# Generated by FakeRAM 2.0 (routing-friendly)
VERSION 5.7 ;
BUSBITCHARS "[]" ;
PROPERTYDEFINITIONS
  MACRO width INTEGER ;
  MACRO depth INTEGER ;
  MACRO banks INTEGER ;
END PROPERTYDEFINITIONS
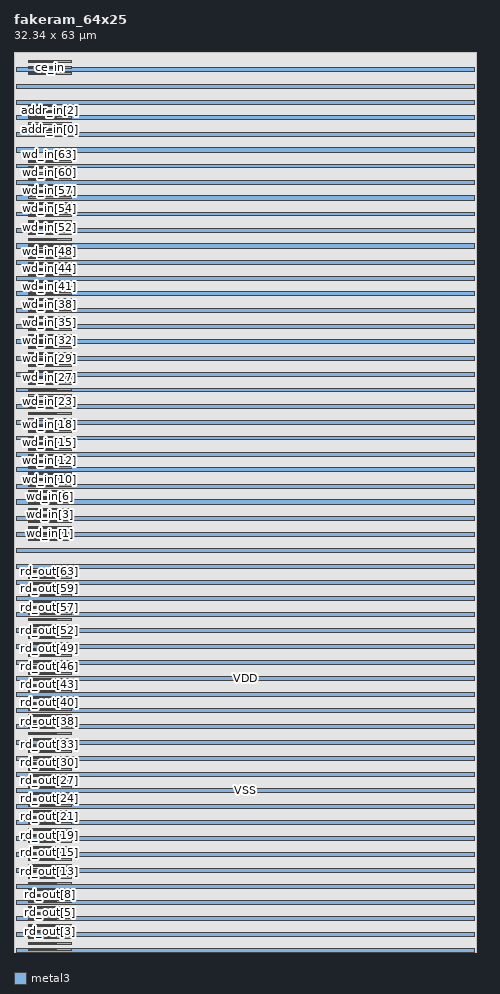
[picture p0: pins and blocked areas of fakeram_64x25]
MACRO fakeram_64x25
  PROPERTY width 64 ;
  PROPERTY depth 25 ;
  PROPERTY banks 1 ;
  FOREIGN fakeram_64x25 0 0 ;
  SYMMETRY X Y R90 ;
  SIZE 32.340 BY 63.000 ;
  CLASS BLOCK ;
  PIN rd_out[0]
    DIRECTION OUTPUT ;
    USE SIGNAL ;
    PORT
      LAYER metal3 ;
      RECT 1.000 0.140 3.000 0.210 ;
    END
    PORT
      LAYER metal3 ;
      RECT 1.000 0.105 4.000 0.245 ;
    END
  END rd_out[0]
  PIN rd_out[1]
    DIRECTION OUTPUT ;
    USE SIGNAL ;
    PORT
      LAYER metal3 ;
      RECT 1.000 0.560 3.000 0.630 ;
    END
    PORT
      LAYER metal3 ;
      RECT 1.000 0.525 4.000 0.665 ;
    END
  END rd_out[1]
  PIN rd_out[2]
    DIRECTION OUTPUT ;
    USE SIGNAL ;
    PORT
      LAYER metal3 ;
      RECT 1.000 0.980 3.000 1.050 ;
    END
    PORT
      LAYER metal3 ;
      RECT 1.000 0.945 4.000 1.085 ;
    END
  END rd_out[2]
  PIN rd_out[3]
    DIRECTION OUTPUT ;
    USE SIGNAL ;
    PORT
      LAYER metal3 ;
      RECT 1.000 1.400 3.000 1.470 ;
    END
    PORT
      LAYER metal3 ;
      RECT 1.000 1.365 4.000 1.505 ;
    END
  END rd_out[3]
  PIN rd_out[4]
    DIRECTION OUTPUT ;
    USE SIGNAL ;
    PORT
      LAYER metal3 ;
      RECT 1.000 1.820 3.000 1.890 ;
    END
    PORT
      LAYER metal3 ;
      RECT 1.000 1.785 4.000 1.925 ;
    END
  END rd_out[4]
  PIN rd_out[5]
    DIRECTION OUTPUT ;
    USE SIGNAL ;
    PORT
      LAYER metal3 ;
      RECT 1.000 2.240 3.000 2.310 ;
    END
    PORT
      LAYER metal3 ;
      RECT 1.000 2.205 4.000 2.345 ;
    END
  END rd_out[5]
  PIN rd_out[6]
    DIRECTION OUTPUT ;
    USE SIGNAL ;
    PORT
      LAYER metal3 ;
      RECT 1.000 2.660 3.000 2.730 ;
    END
    PORT
      LAYER metal3 ;
      RECT 1.000 2.625 4.000 2.765 ;
    END
  END rd_out[6]
  PIN rd_out[7]
    DIRECTION OUTPUT ;
    USE SIGNAL ;
    PORT
      LAYER metal3 ;
      RECT 1.000 3.080 3.000 3.150 ;
    END
    PORT
      LAYER metal3 ;
      RECT 1.000 3.045 4.000 3.185 ;
    END
  END rd_out[7]
  PIN rd_out[8]
    DIRECTION OUTPUT ;
    USE SIGNAL ;
    PORT
      LAYER metal3 ;
      RECT 1.000 3.500 3.000 3.570 ;
    END
    PORT
      LAYER metal3 ;
      RECT 1.000 3.465 4.000 3.605 ;
    END
  END rd_out[8]
  PIN rd_out[9]
    DIRECTION OUTPUT ;
    USE SIGNAL ;
    PORT
      LAYER metal3 ;
      RECT 1.000 3.920 3.000 3.990 ;
    END
    PORT
      LAYER metal3 ;
      RECT 1.000 3.885 4.000 4.025 ;
    END
  END rd_out[9]
  PIN rd_out[10]
    DIRECTION OUTPUT ;
    USE SIGNAL ;
    PORT
      LAYER metal3 ;
      RECT 1.000 4.340 3.000 4.410 ;
    END
    PORT
      LAYER metal3 ;
      RECT 1.000 4.305 4.000 4.445 ;
    END
  END rd_out[10]
  PIN rd_out[11]
    DIRECTION OUTPUT ;
    USE SIGNAL ;
    PORT
      LAYER metal3 ;
      RECT 1.000 4.760 3.000 4.830 ;
    END
    PORT
      LAYER metal3 ;
      RECT 1.000 4.725 4.000 4.865 ;
    END
  END rd_out[11]
  PIN rd_out[12]
    DIRECTION OUTPUT ;
    USE SIGNAL ;
    PORT
      LAYER metal3 ;
      RECT 1.000 5.180 3.000 5.250 ;
    END
    PORT
      LAYER metal3 ;
      RECT 1.000 5.145 4.000 5.285 ;
    END
  END rd_out[12]
  PIN rd_out[13]
    DIRECTION OUTPUT ;
    USE SIGNAL ;
    PORT
      LAYER metal3 ;
      RECT 1.000 5.600 3.000 5.670 ;
    END
    PORT
      LAYER metal3 ;
      RECT 1.000 5.565 4.000 5.705 ;
    END
  END rd_out[13]
  PIN rd_out[14]
    DIRECTION OUTPUT ;
    USE SIGNAL ;
    PORT
      LAYER metal3 ;
      RECT 1.000 6.020 3.000 6.090 ;
    END
    PORT
      LAYER metal3 ;
      RECT 1.000 5.985 4.000 6.125 ;
    END
  END rd_out[14]
  PIN rd_out[15]
    DIRECTION OUTPUT ;
    USE SIGNAL ;
    PORT
      LAYER metal3 ;
      RECT 1.000 6.440 3.000 6.510 ;
    END
    PORT
      LAYER metal3 ;
      RECT 1.000 6.405 4.000 6.545 ;
    END
  END rd_out[15]
  PIN rd_out[16]
    DIRECTION OUTPUT ;
    USE SIGNAL ;
    PORT
      LAYER metal3 ;
      RECT 1.000 6.860 3.000 6.930 ;
    END
    PORT
      LAYER metal3 ;
      RECT 1.000 6.825 4.000 6.965 ;
    END
  END rd_out[16]
  PIN rd_out[17]
    DIRECTION OUTPUT ;
    USE SIGNAL ;
    PORT
      LAYER metal3 ;
      RECT 1.000 7.280 3.000 7.350 ;
    END
    PORT
      LAYER metal3 ;
      RECT 1.000 7.245 4.000 7.385 ;
    END
  END rd_out[17]
  PIN rd_out[18]
    DIRECTION OUTPUT ;
    USE SIGNAL ;
    PORT
      LAYER metal3 ;
      RECT 1.000 7.700 3.000 7.770 ;
    END
    PORT
      LAYER metal3 ;
      RECT 1.000 7.665 4.000 7.805 ;
    END
  END rd_out[18]
  PIN rd_out[19]
    DIRECTION OUTPUT ;
    USE SIGNAL ;
    PORT
      LAYER metal3 ;
      RECT 1.000 8.120 3.000 8.190 ;
    END
    PORT
      LAYER metal3 ;
      RECT 1.000 8.085 4.000 8.225 ;
    END
  END rd_out[19]
  PIN rd_out[20]
    DIRECTION OUTPUT ;
    USE SIGNAL ;
    PORT
      LAYER metal3 ;
      RECT 1.000 8.540 3.000 8.610 ;
    END
    PORT
      LAYER metal3 ;
      RECT 1.000 8.505 4.000 8.645 ;
    END
  END rd_out[20]
  PIN rd_out[21]
    DIRECTION OUTPUT ;
    USE SIGNAL ;
    PORT
      LAYER metal3 ;
      RECT 1.000 8.960 3.000 9.030 ;
    END
    PORT
      LAYER metal3 ;
      RECT 1.000 8.925 4.000 9.065 ;
    END
  END rd_out[21]
  PIN rd_out[22]
    DIRECTION OUTPUT ;
    USE SIGNAL ;
    PORT
      LAYER metal3 ;
      RECT 1.000 9.380 3.000 9.450 ;
    END
    PORT
      LAYER metal3 ;
      RECT 1.000 9.345 4.000 9.485 ;
    END
  END rd_out[22]
  PIN rd_out[23]
    DIRECTION OUTPUT ;
    USE SIGNAL ;
    PORT
      LAYER metal3 ;
      RECT 1.000 9.800 3.000 9.870 ;
    END
    PORT
      LAYER metal3 ;
      RECT 1.000 9.765 4.000 9.905 ;
    END
  END rd_out[23]
  PIN rd_out[24]
    DIRECTION OUTPUT ;
    USE SIGNAL ;
    PORT
      LAYER metal3 ;
      RECT 1.000 10.220 3.000 10.290 ;
    END
    PORT
      LAYER metal3 ;
      RECT 1.000 10.185 4.000 10.325 ;
    END
  END rd_out[24]
  PIN rd_out[25]
    DIRECTION OUTPUT ;
    USE SIGNAL ;
    PORT
      LAYER metal3 ;
      RECT 1.000 10.640 3.000 10.710 ;
    END
    PORT
      LAYER metal3 ;
      RECT 1.000 10.605 4.000 10.745 ;
    END
  END rd_out[25]
  PIN rd_out[26]
    DIRECTION OUTPUT ;
    USE SIGNAL ;
    PORT
      LAYER metal3 ;
      RECT 1.000 11.060 3.000 11.130 ;
    END
    PORT
      LAYER metal3 ;
      RECT 1.000 11.025 4.000 11.165 ;
    END
  END rd_out[26]
  PIN rd_out[27]
    DIRECTION OUTPUT ;
    USE SIGNAL ;
    PORT
      LAYER metal3 ;
      RECT 1.000 11.480 3.000 11.550 ;
    END
    PORT
      LAYER metal3 ;
      RECT 1.000 11.445 4.000 11.585 ;
    END
  END rd_out[27]
  PIN rd_out[28]
    DIRECTION OUTPUT ;
    USE SIGNAL ;
    PORT
      LAYER metal3 ;
      RECT 1.000 11.900 3.000 11.970 ;
    END
    PORT
      LAYER metal3 ;
      RECT 1.000 11.865 4.000 12.005 ;
    END
  END rd_out[28]
  PIN rd_out[29]
    DIRECTION OUTPUT ;
    USE SIGNAL ;
    PORT
      LAYER metal3 ;
      RECT 1.000 12.320 3.000 12.390 ;
    END
    PORT
      LAYER metal3 ;
      RECT 1.000 12.285 4.000 12.425 ;
    END
  END rd_out[29]
  PIN rd_out[30]
    DIRECTION OUTPUT ;
    USE SIGNAL ;
    PORT
      LAYER metal3 ;
      RECT 1.000 12.740 3.000 12.810 ;
    END
    PORT
      LAYER metal3 ;
      RECT 1.000 12.705 4.000 12.845 ;
    END
  END rd_out[30]
  PIN rd_out[31]
    DIRECTION OUTPUT ;
    USE SIGNAL ;
    PORT
      LAYER metal3 ;
      RECT 1.000 13.160 3.000 13.230 ;
    END
    PORT
      LAYER metal3 ;
      RECT 1.000 13.125 4.000 13.265 ;
    END
  END rd_out[31]
  PIN rd_out[32]
    DIRECTION OUTPUT ;
    USE SIGNAL ;
    PORT
      LAYER metal3 ;
      RECT 1.000 13.580 3.000 13.650 ;
    END
    PORT
      LAYER metal3 ;
      RECT 1.000 13.545 4.000 13.685 ;
    END
  END rd_out[32]
  PIN rd_out[33]
    DIRECTION OUTPUT ;
    USE SIGNAL ;
    PORT
      LAYER metal3 ;
      RECT 1.000 14.000 3.000 14.070 ;
    END
    PORT
      LAYER metal3 ;
      RECT 1.000 13.965 4.000 14.105 ;
    END
  END rd_out[33]
  PIN rd_out[34]
    DIRECTION OUTPUT ;
    USE SIGNAL ;
    PORT
      LAYER metal3 ;
      RECT 1.000 14.420 3.000 14.490 ;
    END
    PORT
      LAYER metal3 ;
      RECT 1.000 14.385 4.000 14.525 ;
    END
  END rd_out[34]
  PIN rd_out[35]
    DIRECTION OUTPUT ;
    USE SIGNAL ;
    PORT
      LAYER metal3 ;
      RECT 1.000 14.840 3.000 14.910 ;
    END
    PORT
      LAYER metal3 ;
      RECT 1.000 14.805 4.000 14.945 ;
    END
  END rd_out[35]
  PIN rd_out[36]
    DIRECTION OUTPUT ;
    USE SIGNAL ;
    PORT
      LAYER metal3 ;
      RECT 1.000 15.260 3.000 15.330 ;
    END
    PORT
      LAYER metal3 ;
      RECT 1.000 15.225 4.000 15.365 ;
    END
  END rd_out[36]
  PIN rd_out[37]
    DIRECTION OUTPUT ;
    USE SIGNAL ;
    PORT
      LAYER metal3 ;
      RECT 1.000 15.680 3.000 15.750 ;
    END
    PORT
      LAYER metal3 ;
      RECT 1.000 15.645 4.000 15.785 ;
    END
  END rd_out[37]
  PIN rd_out[38]
    DIRECTION OUTPUT ;
    USE SIGNAL ;
    PORT
      LAYER metal3 ;
      RECT 1.000 16.100 3.000 16.170 ;
    END
    PORT
      LAYER metal3 ;
      RECT 1.000 16.065 4.000 16.205 ;
    END
  END rd_out[38]
  PIN rd_out[39]
    DIRECTION OUTPUT ;
    USE SIGNAL ;
    PORT
      LAYER metal3 ;
      RECT 1.000 16.520 3.000 16.590 ;
    END
    PORT
      LAYER metal3 ;
      RECT 1.000 16.485 4.000 16.625 ;
    END
  END rd_out[39]
  PIN rd_out[40]
    DIRECTION OUTPUT ;
    USE SIGNAL ;
    PORT
      LAYER metal3 ;
      RECT 1.000 16.940 3.000 17.010 ;
    END
    PORT
      LAYER metal3 ;
      RECT 1.000 16.905 4.000 17.045 ;
    END
  END rd_out[40]
  PIN rd_out[41]
    DIRECTION OUTPUT ;
    USE SIGNAL ;
    PORT
      LAYER metal3 ;
      RECT 1.000 17.360 3.000 17.430 ;
    END
    PORT
      LAYER metal3 ;
      RECT 1.000 17.325 4.000 17.465 ;
    END
  END rd_out[41]
  PIN rd_out[42]
    DIRECTION OUTPUT ;
    USE SIGNAL ;
    PORT
      LAYER metal3 ;
      RECT 1.000 17.780 3.000 17.850 ;
    END
    PORT
      LAYER metal3 ;
      RECT 1.000 17.745 4.000 17.885 ;
    END
  END rd_out[42]
  PIN rd_out[43]
    DIRECTION OUTPUT ;
    USE SIGNAL ;
    PORT
      LAYER metal3 ;
      RECT 1.000 18.200 3.000 18.270 ;
    END
    PORT
      LAYER metal3 ;
      RECT 1.000 18.165 4.000 18.305 ;
    END
  END rd_out[43]
  PIN rd_out[44]
    DIRECTION OUTPUT ;
    USE SIGNAL ;
    PORT
      LAYER metal3 ;
      RECT 1.000 18.620 3.000 18.690 ;
    END
    PORT
      LAYER metal3 ;
      RECT 1.000 18.585 4.000 18.725 ;
    END
  END rd_out[44]
  PIN rd_out[45]
    DIRECTION OUTPUT ;
    USE SIGNAL ;
    PORT
      LAYER metal3 ;
      RECT 1.000 19.040 3.000 19.110 ;
    END
    PORT
      LAYER metal3 ;
      RECT 1.000 19.005 4.000 19.145 ;
    END
  END rd_out[45]
  PIN rd_out[46]
    DIRECTION OUTPUT ;
    USE SIGNAL ;
    PORT
      LAYER metal3 ;
      RECT 1.000 19.460 3.000 19.530 ;
    END
    PORT
      LAYER metal3 ;
      RECT 1.000 19.425 4.000 19.565 ;
    END
  END rd_out[46]
  PIN rd_out[47]
    DIRECTION OUTPUT ;
    USE SIGNAL ;
    PORT
      LAYER metal3 ;
      RECT 1.000 19.880 3.000 19.950 ;
    END
    PORT
      LAYER metal3 ;
      RECT 1.000 19.845 4.000 19.985 ;
    END
  END rd_out[47]
  PIN rd_out[48]
    DIRECTION OUTPUT ;
    USE SIGNAL ;
    PORT
      LAYER metal3 ;
      RECT 1.000 20.300 3.000 20.370 ;
    END
    PORT
      LAYER metal3 ;
      RECT 1.000 20.265 4.000 20.405 ;
    END
  END rd_out[48]
  PIN rd_out[49]
    DIRECTION OUTPUT ;
    USE SIGNAL ;
    PORT
      LAYER metal3 ;
      RECT 1.000 20.720 3.000 20.790 ;
    END
    PORT
      LAYER metal3 ;
      RECT 1.000 20.685 4.000 20.825 ;
    END
  END rd_out[49]
  PIN rd_out[50]
    DIRECTION OUTPUT ;
    USE SIGNAL ;
    PORT
      LAYER metal3 ;
      RECT 1.000 21.140 3.000 21.210 ;
    END
    PORT
      LAYER metal3 ;
      RECT 1.000 21.105 4.000 21.245 ;
    END
  END rd_out[50]
  PIN rd_out[51]
    DIRECTION OUTPUT ;
    USE SIGNAL ;
    PORT
      LAYER metal3 ;
      RECT 1.000 21.560 3.000 21.630 ;
    END
    PORT
      LAYER metal3 ;
      RECT 1.000 21.525 4.000 21.665 ;
    END
  END rd_out[51]
  PIN rd_out[52]
    DIRECTION OUTPUT ;
    USE SIGNAL ;
    PORT
      LAYER metal3 ;
      RECT 1.000 21.980 3.000 22.050 ;
    END
    PORT
      LAYER metal3 ;
      RECT 1.000 21.945 4.000 22.085 ;
    END
  END rd_out[52]
  PIN rd_out[53]
    DIRECTION OUTPUT ;
    USE SIGNAL ;
    PORT
      LAYER metal3 ;
      RECT 1.000 22.400 3.000 22.470 ;
    END
    PORT
      LAYER metal3 ;
      RECT 1.000 22.365 4.000 22.505 ;
    END
  END rd_out[53]
  PIN rd_out[54]
    DIRECTION OUTPUT ;
    USE SIGNAL ;
    PORT
      LAYER metal3 ;
      RECT 1.000 22.820 3.000 22.890 ;
    END
    PORT
      LAYER metal3 ;
      RECT 1.000 22.785 4.000 22.925 ;
    END
  END rd_out[54]
  PIN rd_out[55]
    DIRECTION OUTPUT ;
    USE SIGNAL ;
    PORT
      LAYER metal3 ;
      RECT 1.000 23.240 3.000 23.310 ;
    END
    PORT
      LAYER metal3 ;
      RECT 1.000 23.205 4.000 23.345 ;
    END
  END rd_out[55]
  PIN rd_out[56]
    DIRECTION OUTPUT ;
    USE SIGNAL ;
    PORT
      LAYER metal3 ;
      RECT 1.000 23.660 3.000 23.730 ;
    END
    PORT
      LAYER metal3 ;
      RECT 1.000 23.625 4.000 23.765 ;
    END
  END rd_out[56]
  PIN rd_out[57]
    DIRECTION OUTPUT ;
    USE SIGNAL ;
    PORT
      LAYER metal3 ;
      RECT 1.000 24.080 3.000 24.150 ;
    END
    PORT
      LAYER metal3 ;
      RECT 1.000 24.045 4.000 24.185 ;
    END
  END rd_out[57]
  PIN rd_out[58]
    DIRECTION OUTPUT ;
    USE SIGNAL ;
    PORT
      LAYER metal3 ;
      RECT 1.000 24.500 3.000 24.570 ;
    END
    PORT
      LAYER metal3 ;
      RECT 1.000 24.465 4.000 24.605 ;
    END
  END rd_out[58]
  PIN rd_out[59]
    DIRECTION OUTPUT ;
    USE SIGNAL ;
    PORT
      LAYER metal3 ;
      RECT 1.000 24.920 3.000 24.990 ;
    END
    PORT
      LAYER metal3 ;
      RECT 1.000 24.885 4.000 25.025 ;
    END
  END rd_out[59]
  PIN rd_out[60]
    DIRECTION OUTPUT ;
    USE SIGNAL ;
    PORT
      LAYER metal3 ;
      RECT 1.000 25.340 3.000 25.410 ;
    END
    PORT
      LAYER metal3 ;
      RECT 1.000 25.305 4.000 25.445 ;
    END
  END rd_out[60]
  PIN rd_out[61]
    DIRECTION OUTPUT ;
    USE SIGNAL ;
    PORT
      LAYER metal3 ;
      RECT 1.000 25.760 3.000 25.830 ;
    END
    PORT
      LAYER metal3 ;
      RECT 1.000 25.725 4.000 25.865 ;
    END
  END rd_out[61]
  PIN rd_out[62]
    DIRECTION OUTPUT ;
    USE SIGNAL ;
    PORT
      LAYER metal3 ;
      RECT 1.000 26.180 3.000 26.250 ;
    END
    PORT
      LAYER metal3 ;
      RECT 1.000 26.145 4.000 26.285 ;
    END
  END rd_out[62]
  PIN rd_out[63]
    DIRECTION OUTPUT ;
    USE SIGNAL ;
    PORT
      LAYER metal3 ;
      RECT 1.000 26.600 3.000 26.670 ;
    END
    PORT
      LAYER metal3 ;
      RECT 1.000 26.565 4.000 26.705 ;
    END
  END rd_out[63]
  PIN wd_in[0]
    DIRECTION INPUT ;
    USE SIGNAL ;
    PORT
      LAYER metal3 ;
      RECT 1.000 28.840 3.000 28.910 ;
    END
    PORT
      LAYER metal3 ;
      RECT 1.000 28.805 4.000 28.945 ;
    END
  END wd_in[0]
  PIN wd_in[1]
    DIRECTION INPUT ;
    USE SIGNAL ;
    PORT
      LAYER metal3 ;
      RECT 1.000 29.260 3.000 29.330 ;
    END
    PORT
      LAYER metal3 ;
      RECT 1.000 29.225 4.000 29.365 ;
    END
  END wd_in[1]
  PIN wd_in[2]
    DIRECTION INPUT ;
    USE SIGNAL ;
    PORT
      LAYER metal3 ;
      RECT 1.000 29.680 3.000 29.750 ;
    END
    PORT
      LAYER metal3 ;
      RECT 1.000 29.645 4.000 29.785 ;
    END
  END wd_in[2]
  PIN wd_in[3]
    DIRECTION INPUT ;
    USE SIGNAL ;
    PORT
      LAYER metal3 ;
      RECT 1.000 30.100 3.000 30.170 ;
    END
    PORT
      LAYER metal3 ;
      RECT 1.000 30.065 4.000 30.205 ;
    END
  END wd_in[3]
  PIN wd_in[4]
    DIRECTION INPUT ;
    USE SIGNAL ;
    PORT
      LAYER metal3 ;
      RECT 1.000 30.520 3.000 30.590 ;
    END
    PORT
      LAYER metal3 ;
      RECT 1.000 30.485 4.000 30.625 ;
    END
  END wd_in[4]
  PIN wd_in[5]
    DIRECTION INPUT ;
    USE SIGNAL ;
    PORT
      LAYER metal3 ;
      RECT 1.000 30.940 3.000 31.010 ;
    END
    PORT
      LAYER metal3 ;
      RECT 1.000 30.905 4.000 31.045 ;
    END
  END wd_in[5]
  PIN wd_in[6]
    DIRECTION INPUT ;
    USE SIGNAL ;
    PORT
      LAYER metal3 ;
      RECT 1.000 31.360 3.000 31.430 ;
    END
    PORT
      LAYER metal3 ;
      RECT 1.000 31.325 4.000 31.465 ;
    END
  END wd_in[6]
  PIN wd_in[7]
    DIRECTION INPUT ;
    USE SIGNAL ;
    PORT
      LAYER metal3 ;
      RECT 1.000 31.780 3.000 31.850 ;
    END
    PORT
      LAYER metal3 ;
      RECT 1.000 31.745 4.000 31.885 ;
    END
  END wd_in[7]
  PIN wd_in[8]
    DIRECTION INPUT ;
    USE SIGNAL ;
    PORT
      LAYER metal3 ;
      RECT 1.000 32.200 3.000 32.270 ;
    END
    PORT
      LAYER metal3 ;
      RECT 1.000 32.165 4.000 32.305 ;
    END
  END wd_in[8]
  PIN wd_in[9]
    DIRECTION INPUT ;
    USE SIGNAL ;
    PORT
      LAYER metal3 ;
      RECT 1.000 32.620 3.000 32.690 ;
    END
    PORT
      LAYER metal3 ;
      RECT 1.000 32.585 4.000 32.725 ;
    END
  END wd_in[9]
  PIN wd_in[10]
    DIRECTION INPUT ;
    USE SIGNAL ;
    PORT
      LAYER metal3 ;
      RECT 1.000 33.040 3.000 33.110 ;
    END
    PORT
      LAYER metal3 ;
      RECT 1.000 33.005 4.000 33.145 ;
    END
  END wd_in[10]
  PIN wd_in[11]
    DIRECTION INPUT ;
    USE SIGNAL ;
    PORT
      LAYER metal3 ;
      RECT 1.000 33.460 3.000 33.530 ;
    END
    PORT
      LAYER metal3 ;
      RECT 1.000 33.425 4.000 33.565 ;
    END
  END wd_in[11]
  PIN wd_in[12]
    DIRECTION INPUT ;
    USE SIGNAL ;
    PORT
      LAYER metal3 ;
      RECT 1.000 33.880 3.000 33.950 ;
    END
    PORT
      LAYER metal3 ;
      RECT 1.000 33.845 4.000 33.985 ;
    END
  END wd_in[12]
  PIN wd_in[13]
    DIRECTION INPUT ;
    USE SIGNAL ;
    PORT
      LAYER metal3 ;
      RECT 1.000 34.300 3.000 34.370 ;
    END
    PORT
      LAYER metal3 ;
      RECT 1.000 34.265 4.000 34.405 ;
    END
  END wd_in[13]
  PIN wd_in[14]
    DIRECTION INPUT ;
    USE SIGNAL ;
    PORT
      LAYER metal3 ;
      RECT 1.000 34.720 3.000 34.790 ;
    END
    PORT
      LAYER metal3 ;
      RECT 1.000 34.685 4.000 34.825 ;
    END
  END wd_in[14]
  PIN wd_in[15]
    DIRECTION INPUT ;
    USE SIGNAL ;
    PORT
      LAYER metal3 ;
      RECT 1.000 35.140 3.000 35.210 ;
    END
    PORT
      LAYER metal3 ;
      RECT 1.000 35.105 4.000 35.245 ;
    END
  END wd_in[15]
  PIN wd_in[16]
    DIRECTION INPUT ;
    USE SIGNAL ;
    PORT
      LAYER metal3 ;
      RECT 1.000 35.560 3.000 35.630 ;
    END
    PORT
      LAYER metal3 ;
      RECT 1.000 35.525 4.000 35.665 ;
    END
  END wd_in[16]
  PIN wd_in[17]
    DIRECTION INPUT ;
    USE SIGNAL ;
    PORT
      LAYER metal3 ;
      RECT 1.000 35.980 3.000 36.050 ;
    END
    PORT
      LAYER metal3 ;
      RECT 1.000 35.945 4.000 36.085 ;
    END
  END wd_in[17]
  PIN wd_in[18]
    DIRECTION INPUT ;
    USE SIGNAL ;
    PORT
      LAYER metal3 ;
      RECT 1.000 36.400 3.000 36.470 ;
    END
    PORT
      LAYER metal3 ;
      RECT 1.000 36.365 4.000 36.505 ;
    END
  END wd_in[18]
  PIN wd_in[19]
    DIRECTION INPUT ;
    USE SIGNAL ;
    PORT
      LAYER metal3 ;
      RECT 1.000 36.820 3.000 36.890 ;
    END
    PORT
      LAYER metal3 ;
      RECT 1.000 36.785 4.000 36.925 ;
    END
  END wd_in[19]
  PIN wd_in[20]
    DIRECTION INPUT ;
    USE SIGNAL ;
    PORT
      LAYER metal3 ;
      RECT 1.000 37.240 3.000 37.310 ;
    END
    PORT
      LAYER metal3 ;
      RECT 1.000 37.205 4.000 37.345 ;
    END
  END wd_in[20]
  PIN wd_in[21]
    DIRECTION INPUT ;
    USE SIGNAL ;
    PORT
      LAYER metal3 ;
      RECT 1.000 37.660 3.000 37.730 ;
    END
    PORT
      LAYER metal3 ;
      RECT 1.000 37.625 4.000 37.765 ;
    END
  END wd_in[21]
  PIN wd_in[22]
    DIRECTION INPUT ;
    USE SIGNAL ;
    PORT
      LAYER metal3 ;
      RECT 1.000 38.080 3.000 38.150 ;
    END
    PORT
      LAYER metal3 ;
      RECT 1.000 38.045 4.000 38.185 ;
    END
  END wd_in[22]
  PIN wd_in[23]
    DIRECTION INPUT ;
    USE SIGNAL ;
    PORT
      LAYER metal3 ;
      RECT 1.000 38.500 3.000 38.570 ;
    END
    PORT
      LAYER metal3 ;
      RECT 1.000 38.465 4.000 38.605 ;
    END
  END wd_in[23]
  PIN wd_in[24]
    DIRECTION INPUT ;
    USE SIGNAL ;
    PORT
      LAYER metal3 ;
      RECT 1.000 38.920 3.000 38.990 ;
    END
    PORT
      LAYER metal3 ;
      RECT 1.000 38.885 4.000 39.025 ;
    END
  END wd_in[24]
  PIN wd_in[25]
    DIRECTION INPUT ;
    USE SIGNAL ;
    PORT
      LAYER metal3 ;
      RECT 1.000 39.340 3.000 39.410 ;
    END
    PORT
      LAYER metal3 ;
      RECT 1.000 39.305 4.000 39.445 ;
    END
  END wd_in[25]
  PIN wd_in[26]
    DIRECTION INPUT ;
    USE SIGNAL ;
    PORT
      LAYER metal3 ;
      RECT 1.000 39.760 3.000 39.830 ;
    END
    PORT
      LAYER metal3 ;
      RECT 1.000 39.725 4.000 39.865 ;
    END
  END wd_in[26]
  PIN wd_in[27]
    DIRECTION INPUT ;
    USE SIGNAL ;
    PORT
      LAYER metal3 ;
      RECT 1.000 40.180 3.000 40.250 ;
    END
    PORT
      LAYER metal3 ;
      RECT 1.000 40.145 4.000 40.285 ;
    END
  END wd_in[27]
  PIN wd_in[28]
    DIRECTION INPUT ;
    USE SIGNAL ;
    PORT
      LAYER metal3 ;
      RECT 1.000 40.600 3.000 40.670 ;
    END
    PORT
      LAYER metal3 ;
      RECT 1.000 40.565 4.000 40.705 ;
    END
  END wd_in[28]
  PIN wd_in[29]
    DIRECTION INPUT ;
    USE SIGNAL ;
    PORT
      LAYER metal3 ;
      RECT 1.000 41.020 3.000 41.090 ;
    END
    PORT
      LAYER metal3 ;
      RECT 1.000 40.985 4.000 41.125 ;
    END
  END wd_in[29]
  PIN wd_in[30]
    DIRECTION INPUT ;
    USE SIGNAL ;
    PORT
      LAYER metal3 ;
      RECT 1.000 41.440 3.000 41.510 ;
    END
    PORT
      LAYER metal3 ;
      RECT 1.000 41.405 4.000 41.545 ;
    END
  END wd_in[30]
  PIN wd_in[31]
    DIRECTION INPUT ;
    USE SIGNAL ;
    PORT
      LAYER metal3 ;
      RECT 1.000 41.860 3.000 41.930 ;
    END
    PORT
      LAYER metal3 ;
      RECT 1.000 41.825 4.000 41.965 ;
    END
  END wd_in[31]
  PIN wd_in[32]
    DIRECTION INPUT ;
    USE SIGNAL ;
    PORT
      LAYER metal3 ;
      RECT 1.000 42.280 3.000 42.350 ;
    END
    PORT
      LAYER metal3 ;
      RECT 1.000 42.245 4.000 42.385 ;
    END
  END wd_in[32]
  PIN wd_in[33]
    DIRECTION INPUT ;
    USE SIGNAL ;
    PORT
      LAYER metal3 ;
      RECT 1.000 42.700 3.000 42.770 ;
    END
    PORT
      LAYER metal3 ;
      RECT 1.000 42.665 4.000 42.805 ;
    END
  END wd_in[33]
  PIN wd_in[34]
    DIRECTION INPUT ;
    USE SIGNAL ;
    PORT
      LAYER metal3 ;
      RECT 1.000 43.120 3.000 43.190 ;
    END
    PORT
      LAYER metal3 ;
      RECT 1.000 43.085 4.000 43.225 ;
    END
  END wd_in[34]
  PIN wd_in[35]
    DIRECTION INPUT ;
    USE SIGNAL ;
    PORT
      LAYER metal3 ;
      RECT 1.000 43.540 3.000 43.610 ;
    END
    PORT
      LAYER metal3 ;
      RECT 1.000 43.505 4.000 43.645 ;
    END
  END wd_in[35]
  PIN wd_in[36]
    DIRECTION INPUT ;
    USE SIGNAL ;
    PORT
      LAYER metal3 ;
      RECT 1.000 43.960 3.000 44.030 ;
    END
    PORT
      LAYER metal3 ;
      RECT 1.000 43.925 4.000 44.065 ;
    END
  END wd_in[36]
  PIN wd_in[37]
    DIRECTION INPUT ;
    USE SIGNAL ;
    PORT
      LAYER metal3 ;
      RECT 1.000 44.380 3.000 44.450 ;
    END
    PORT
      LAYER metal3 ;
      RECT 1.000 44.345 4.000 44.485 ;
    END
  END wd_in[37]
  PIN wd_in[38]
    DIRECTION INPUT ;
    USE SIGNAL ;
    PORT
      LAYER metal3 ;
      RECT 1.000 44.800 3.000 44.870 ;
    END
    PORT
      LAYER metal3 ;
      RECT 1.000 44.765 4.000 44.905 ;
    END
  END wd_in[38]
  PIN wd_in[39]
    DIRECTION INPUT ;
    USE SIGNAL ;
    PORT
      LAYER metal3 ;
      RECT 1.000 45.220 3.000 45.290 ;
    END
    PORT
      LAYER metal3 ;
      RECT 1.000 45.185 4.000 45.325 ;
    END
  END wd_in[39]
  PIN wd_in[40]
    DIRECTION INPUT ;
    USE SIGNAL ;
    PORT
      LAYER metal3 ;
      RECT 1.000 45.640 3.000 45.710 ;
    END
    PORT
      LAYER metal3 ;
      RECT 1.000 45.605 4.000 45.745 ;
    END
  END wd_in[40]
  PIN wd_in[41]
    DIRECTION INPUT ;
    USE SIGNAL ;
    PORT
      LAYER metal3 ;
      RECT 1.000 46.060 3.000 46.130 ;
    END
    PORT
      LAYER metal3 ;
      RECT 1.000 46.025 4.000 46.165 ;
    END
  END wd_in[41]
  PIN wd_in[42]
    DIRECTION INPUT ;
    USE SIGNAL ;
    PORT
      LAYER metal3 ;
      RECT 1.000 46.480 3.000 46.550 ;
    END
    PORT
      LAYER metal3 ;
      RECT 1.000 46.445 4.000 46.585 ;
    END
  END wd_in[42]
  PIN wd_in[43]
    DIRECTION INPUT ;
    USE SIGNAL ;
    PORT
      LAYER metal3 ;
      RECT 1.000 46.900 3.000 46.970 ;
    END
    PORT
      LAYER metal3 ;
      RECT 1.000 46.865 4.000 47.005 ;
    END
  END wd_in[43]
  PIN wd_in[44]
    DIRECTION INPUT ;
    USE SIGNAL ;
    PORT
      LAYER metal3 ;
      RECT 1.000 47.320 3.000 47.390 ;
    END
    PORT
      LAYER metal3 ;
      RECT 1.000 47.285 4.000 47.425 ;
    END
  END wd_in[44]
  PIN wd_in[45]
    DIRECTION INPUT ;
    USE SIGNAL ;
    PORT
      LAYER metal3 ;
      RECT 1.000 47.740 3.000 47.810 ;
    END
    PORT
      LAYER metal3 ;
      RECT 1.000 47.705 4.000 47.845 ;
    END
  END wd_in[45]
  PIN wd_in[46]
    DIRECTION INPUT ;
    USE SIGNAL ;
    PORT
      LAYER metal3 ;
      RECT 1.000 48.160 3.000 48.230 ;
    END
    PORT
      LAYER metal3 ;
      RECT 1.000 48.125 4.000 48.265 ;
    END
  END wd_in[46]
  PIN wd_in[47]
    DIRECTION INPUT ;
    USE SIGNAL ;
    PORT
      LAYER metal3 ;
      RECT 1.000 48.580 3.000 48.650 ;
    END
    PORT
      LAYER metal3 ;
      RECT 1.000 48.545 4.000 48.685 ;
    END
  END wd_in[47]
  PIN wd_in[48]
    DIRECTION INPUT ;
    USE SIGNAL ;
    PORT
      LAYER metal3 ;
      RECT 1.000 49.000 3.000 49.070 ;
    END
    PORT
      LAYER metal3 ;
      RECT 1.000 48.965 4.000 49.105 ;
    END
  END wd_in[48]
  PIN wd_in[49]
    DIRECTION INPUT ;
    USE SIGNAL ;
    PORT
      LAYER metal3 ;
      RECT 1.000 49.420 3.000 49.490 ;
    END
    PORT
      LAYER metal3 ;
      RECT 1.000 49.385 4.000 49.525 ;
    END
  END wd_in[49]
  PIN wd_in[50]
    DIRECTION INPUT ;
    USE SIGNAL ;
    PORT
      LAYER metal3 ;
      RECT 1.000 49.840 3.000 49.910 ;
    END
    PORT
      LAYER metal3 ;
      RECT 1.000 49.805 4.000 49.945 ;
    END
  END wd_in[50]
  PIN wd_in[51]
    DIRECTION INPUT ;
    USE SIGNAL ;
    PORT
      LAYER metal3 ;
      RECT 1.000 50.260 3.000 50.330 ;
    END
    PORT
      LAYER metal3 ;
      RECT 1.000 50.225 4.000 50.365 ;
    END
  END wd_in[51]
  PIN wd_in[52]
    DIRECTION INPUT ;
    USE SIGNAL ;
    PORT
      LAYER metal3 ;
      RECT 1.000 50.680 3.000 50.750 ;
    END
    PORT
      LAYER metal3 ;
      RECT 1.000 50.645 4.000 50.785 ;
    END
  END wd_in[52]
  PIN wd_in[53]
    DIRECTION INPUT ;
    USE SIGNAL ;
    PORT
      LAYER metal3 ;
      RECT 1.000 51.100 3.000 51.170 ;
    END
    PORT
      LAYER metal3 ;
      RECT 1.000 51.065 4.000 51.205 ;
    END
  END wd_in[53]
  PIN wd_in[54]
    DIRECTION INPUT ;
    USE SIGNAL ;
    PORT
      LAYER metal3 ;
      RECT 1.000 51.520 3.000 51.590 ;
    END
    PORT
      LAYER metal3 ;
      RECT 1.000 51.485 4.000 51.625 ;
    END
  END wd_in[54]
  PIN wd_in[55]
    DIRECTION INPUT ;
    USE SIGNAL ;
    PORT
      LAYER metal3 ;
      RECT 1.000 51.940 3.000 52.010 ;
    END
    PORT
      LAYER metal3 ;
      RECT 1.000 51.905 4.000 52.045 ;
    END
  END wd_in[55]
  PIN wd_in[56]
    DIRECTION INPUT ;
    USE SIGNAL ;
    PORT
      LAYER metal3 ;
      RECT 1.000 52.360 3.000 52.430 ;
    END
    PORT
      LAYER metal3 ;
      RECT 1.000 52.325 4.000 52.465 ;
    END
  END wd_in[56]
  PIN wd_in[57]
    DIRECTION INPUT ;
    USE SIGNAL ;
    PORT
      LAYER metal3 ;
      RECT 1.000 52.780 3.000 52.850 ;
    END
    PORT
      LAYER metal3 ;
      RECT 1.000 52.745 4.000 52.885 ;
    END
  END wd_in[57]
  PIN wd_in[58]
    DIRECTION INPUT ;
    USE SIGNAL ;
    PORT
      LAYER metal3 ;
      RECT 1.000 53.200 3.000 53.270 ;
    END
    PORT
      LAYER metal3 ;
      RECT 1.000 53.165 4.000 53.305 ;
    END
  END wd_in[58]
  PIN wd_in[59]
    DIRECTION INPUT ;
    USE SIGNAL ;
    PORT
      LAYER metal3 ;
      RECT 1.000 53.620 3.000 53.690 ;
    END
    PORT
      LAYER metal3 ;
      RECT 1.000 53.585 4.000 53.725 ;
    END
  END wd_in[59]
  PIN wd_in[60]
    DIRECTION INPUT ;
    USE SIGNAL ;
    PORT
      LAYER metal3 ;
      RECT 1.000 54.040 3.000 54.110 ;
    END
    PORT
      LAYER metal3 ;
      RECT 1.000 54.005 4.000 54.145 ;
    END
  END wd_in[60]
  PIN wd_in[61]
    DIRECTION INPUT ;
    USE SIGNAL ;
    PORT
      LAYER metal3 ;
      RECT 1.000 54.460 3.000 54.530 ;
    END
    PORT
      LAYER metal3 ;
      RECT 1.000 54.425 4.000 54.565 ;
    END
  END wd_in[61]
  PIN wd_in[62]
    DIRECTION INPUT ;
    USE SIGNAL ;
    PORT
      LAYER metal3 ;
      RECT 1.000 54.880 3.000 54.950 ;
    END
    PORT
      LAYER metal3 ;
      RECT 1.000 54.845 4.000 54.985 ;
    END
  END wd_in[62]
  PIN wd_in[63]
    DIRECTION INPUT ;
    USE SIGNAL ;
    PORT
      LAYER metal3 ;
      RECT 1.000 55.300 3.000 55.370 ;
    END
    PORT
      LAYER metal3 ;
      RECT 1.000 55.265 4.000 55.405 ;
    END
  END wd_in[63]
  PIN addr_in[0]
    DIRECTION INPUT ;
    USE SIGNAL ;
    PORT
      LAYER metal3 ;
      RECT 1.000 57.540 3.000 57.610 ;
    END
    PORT
      LAYER metal3 ;
      RECT 1.000 57.505 4.000 57.645 ;
    END
  END addr_in[0]
  PIN addr_in[1]
    DIRECTION INPUT ;
    USE SIGNAL ;
    PORT
      LAYER metal3 ;
      RECT 1.000 57.960 3.000 58.030 ;
    END
    PORT
      LAYER metal3 ;
      RECT 1.000 57.925 4.000 58.065 ;
    END
  END addr_in[1]
  PIN addr_in[2]
    DIRECTION INPUT ;
    USE SIGNAL ;
    PORT
      LAYER metal3 ;
      RECT 1.000 58.380 3.000 58.450 ;
    END
    PORT
      LAYER metal3 ;
      RECT 1.000 58.345 4.000 58.485 ;
    END
  END addr_in[2]
  PIN addr_in[3]
    DIRECTION INPUT ;
    USE SIGNAL ;
    PORT
      LAYER metal3 ;
      RECT 1.000 58.800 3.000 58.870 ;
    END
    PORT
      LAYER metal3 ;
      RECT 1.000 58.765 4.000 58.905 ;
    END
  END addr_in[3]
  PIN addr_in[4]
    DIRECTION INPUT ;
    USE SIGNAL ;
    PORT
      LAYER metal3 ;
      RECT 1.000 59.220 3.000 59.290 ;
    END
    PORT
      LAYER metal3 ;
      RECT 1.000 59.185 4.000 59.325 ;
    END
  END addr_in[4]
  PIN we_in
    DIRECTION INPUT ;
    USE SIGNAL ;
    PORT
      LAYER metal3 ;
      RECT 1.000 61.460 3.000 61.530 ;
    END
    PORT
      LAYER metal3 ;
      RECT 1.000 61.425 4.000 61.565 ;
    END
  END we_in
  PIN ce_in
    DIRECTION INPUT ;
    USE SIGNAL ;
    PORT
      LAYER metal3 ;
      RECT 1.000 61.880 3.000 61.950 ;
    END
    PORT
      LAYER metal3 ;
      RECT 1.000 61.845 4.000 61.985 ;
    END
  END ce_in
  PIN clk
    DIRECTION INPUT ;
    USE SIGNAL ;
    PORT
      LAYER metal3 ;
      RECT 1.000 62.300 3.000 62.370 ;
    END
    PORT
      LAYER metal3 ;
      RECT 1.000 62.265 4.000 62.405 ;
    END
  END clk
  PIN VSS
    DIRECTION INOUT ;
    USE GROUND ;
    PORT
      LAYER metal3 ;
      RECT 0.140 0.000 32.200 0.280 ;
      RECT 0.140 2.240 32.200 2.520 ;
      RECT 0.140 4.480 32.200 4.760 ;
      RECT 0.140 6.720 32.200 7.000 ;
      RECT 0.140 8.960 32.200 9.240 ;
      RECT 0.140 11.200 32.200 11.480 ;
      RECT 0.140 13.440 32.200 13.720 ;
      RECT 0.140 15.680 32.200 15.960 ;
      RECT 0.140 17.920 32.200 18.200 ;
      RECT 0.140 20.160 32.200 20.440 ;
      RECT 0.140 22.400 32.200 22.680 ;
      RECT 0.140 24.640 32.200 24.920 ;
      RECT 0.140 26.880 32.200 27.160 ;
      RECT 0.140 29.120 32.200 29.400 ;
      RECT 0.140 31.360 32.200 31.640 ;
      RECT 0.140 33.600 32.200 33.880 ;
      RECT 0.140 35.840 32.200 36.120 ;
      RECT 0.140 38.080 32.200 38.360 ;
      RECT 0.140 40.320 32.200 40.600 ;
      RECT 0.140 42.560 32.200 42.840 ;
      RECT 0.140 44.800 32.200 45.080 ;
      RECT 0.140 47.040 32.200 47.320 ;
      RECT 0.140 49.280 32.200 49.560 ;
      RECT 0.140 51.520 32.200 51.800 ;
      RECT 0.140 53.760 32.200 54.040 ;
      RECT 0.140 56.000 32.200 56.280 ;
      RECT 0.140 58.240 32.200 58.520 ;
      RECT 0.140 60.480 32.200 60.760 ;
    END
  END VSS
  PIN VDD
    DIRECTION INOUT ;
    USE POWER ;
    PORT
      LAYER metal3 ;
      RECT 0.140 1.120 32.200 1.400 ;
      RECT 0.140 3.360 32.200 3.640 ;
      RECT 0.140 5.600 32.200 5.880 ;
      RECT 0.140 7.840 32.200 8.120 ;
      RECT 0.140 10.080 32.200 10.360 ;
      RECT 0.140 12.320 32.200 12.600 ;
      RECT 0.140 14.560 32.200 14.840 ;
      RECT 0.140 16.800 32.200 17.080 ;
      RECT 0.140 19.040 32.200 19.320 ;
      RECT 0.140 21.280 32.200 21.560 ;
      RECT 0.140 23.520 32.200 23.800 ;
      RECT 0.140 25.760 32.200 26.040 ;
      RECT 0.140 28.000 32.200 28.280 ;
      RECT 0.140 30.240 32.200 30.520 ;
      RECT 0.140 32.480 32.200 32.760 ;
      RECT 0.140 34.720 32.200 35.000 ;
      RECT 0.140 36.960 32.200 37.240 ;
      RECT 0.140 39.200 32.200 39.480 ;
      RECT 0.140 41.440 32.200 41.720 ;
      RECT 0.140 43.680 32.200 43.960 ;
      RECT 0.140 45.920 32.200 46.200 ;
      RECT 0.140 48.160 32.200 48.440 ;
      RECT 0.140 50.400 32.200 50.680 ;
      RECT 0.140 52.640 32.200 52.920 ;
      RECT 0.140 54.880 32.200 55.160 ;
      RECT 0.140 57.120 32.200 57.400 ;
      RECT 0.140 59.360 32.200 59.640 ;
      RECT 0.140 61.600 32.200 61.880 ;
    END
  END VDD
  OBS
    LAYER metal1 ;
    RECT 0 0 32.340 63.000 ;
    LAYER metal2 ;
    RECT 0 0 32.340 63.000 ;
  END
END fakeram_64x25
END LIBRARY
